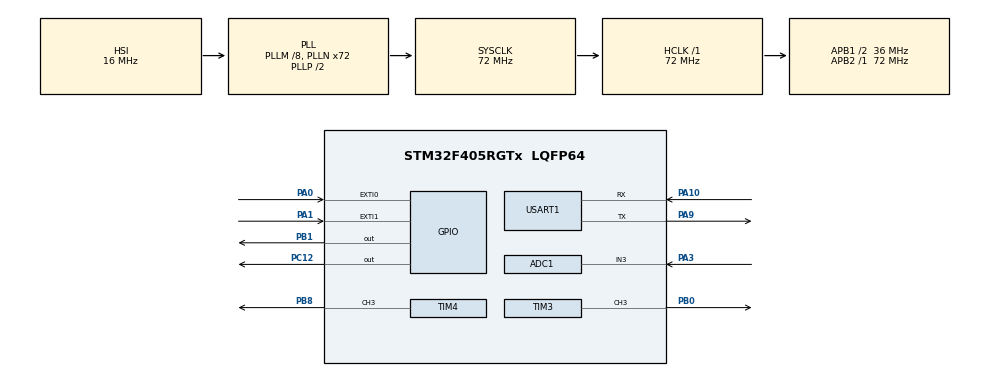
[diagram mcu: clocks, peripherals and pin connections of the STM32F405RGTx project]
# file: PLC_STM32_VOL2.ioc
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ADC1.Channel-0\#ChannelRegularConversion=ADC_CHANNEL_3
ADC1.ExternalTrigConv=ADC_EXTERNALTRIGCONV_T1_CC1
ADC1.NbrOfConversionFlag=1
ADC1.Rank-0\#ChannelRegularConversion=1
ADC1.SamplingTime-0\#ChannelRegularConversion=ADC_SAMPLETIME_3CYCLES
ADC1.master=1
Dma.Request0=TIM3_CH4/UP
Dma.Request1=TIM4_UP
Dma.Request2=USART1_TX
Dma.Request3=TIM4_CH3
Dma.TIM3_CH4/UP.0.Direction=DMA_MEMORY_TO_PERIPH
Dma.TIM3_CH4/UP.0.FIFOMode=DMA_FIFOMODE_DISABLE
Dma.TIM3_CH4/UP.0.Instance=DMA1_Stream2
Dma.TIM3_CH4/UP.0.MemDataAlignment=DMA_MDATAALIGN_HALFWORD
Dma.TIM3_CH4/UP.0.MemInc=DMA_MINC_ENABLE
Dma.TIM3_CH4/UP.0.Mode=DMA_NORMAL
Dma.TIM3_CH4/UP.0.PeriphDataAlignment=DMA_PDATAALIGN_HALFWORD
Dma.TIM3_CH4/UP.0.PeriphInc=DMA_PINC_DISABLE
Dma.TIM3_CH4/UP.0.Priority=DMA_PRIORITY_LOW
Dma.TIM4_CH3.3.Direction=DMA_MEMORY_TO_PERIPH
Dma.TIM4_CH3.3.FIFOMode=DMA_FIFOMODE_DISABLE
Dma.TIM4_CH3.3.Instance=DMA1_Stream7
Dma.TIM4_CH3.3.MemDataAlignment=DMA_MDATAALIGN_HALFWORD
Dma.TIM4_CH3.3.MemInc=DMA_MINC_ENABLE
Dma.TIM4_CH3.3.Mode=DMA_NORMAL
Dma.TIM4_CH3.3.PeriphDataAlignment=DMA_PDATAALIGN_HALFWORD
Dma.TIM4_CH3.3.PeriphInc=DMA_PINC_DISABLE
Dma.TIM4_CH3.3.Priority=DMA_PRIORITY_LOW
Dma.TIM4_UP.1.Direction=DMA_MEMORY_TO_PERIPH
Dma.TIM4_UP.1.FIFOMode=DMA_FIFOMODE_DISABLE
Dma.TIM4_UP.1.Instance=DMA1_Stream6
Dma.TIM4_UP.1.MemDataAlignment=DMA_MDATAALIGN_HALFWORD
Dma.TIM4_UP.1.MemInc=DMA_MINC_ENABLE
Dma.TIM4_UP.1.Mode=DMA_NORMAL
Dma.TIM4_UP.1.PeriphDataAlignment=DMA_PDATAALIGN_HALFWORD
Dma.TIM4_UP.1.PeriphInc=DMA_PINC_DISABLE
Dma.TIM4_UP.1.Priority=DMA_PRIORITY_LOW
Dma.USART1_TX.2.Direction=DMA_MEMORY_TO_PERIPH
Dma.USART1_TX.2.FIFOMode=DMA_FIFOMODE_DISABLE
Dma.USART1_TX.2.Instance=DMA2_Stream7
Dma.USART1_TX.2.MemDataAlignment=DMA_MDATAALIGN_BYTE
Dma.USART1_TX.2.MemInc=DMA_MINC_ENABLE
Dma.USART1_TX.2.Mode=DMA_NORMAL
Dma.USART1_TX.2.PeriphDataAlignment=DMA_PDATAALIGN_BYTE
Dma.USART1_TX.2.PeriphInc=DMA_PINC_DISABLE
Dma.USART1_TX.2.Priority=DMA_PRIORITY_LOW
Mcu.Family=STM32F4
Mcu.Name=STM32F405RGTx
Mcu.Package=LQFP64
NVIC.ADC_IRQn=true\:0\:0\:false\:false\:true\:true\:true\:true
NVIC.DMA1_Stream2_IRQn=true\:0\:0\:false\:false\:true\:false\:true\:true
NVIC.DMA1_Stream6_IRQn=true\:0\:0\:false\:false\:true\:false\:true\:true
NVIC.DMA1_Stream7_IRQn=true\:0\:0\:false\:false\:true\:false\:true\:true
NVIC.DMA2_Stream7_IRQn=true\:0\:0\:false\:false\:true\:false\:true\:true
NVIC.PriorityGroup=NVIC_PRIORITYGROUP_4
NVIC.TIM1_TRG_COM_TIM11_IRQn=true\:0\:0\:false\:false\:true\:true\:true\:true
NVIC.TIM1_UP_TIM10_IRQn=true\:0\:0\:false\:false\:true\:true\:true\:true
NVIC.TIM2_IRQn=true\:0\:0\:false\:false\:true\:true\:true\:true
NVIC.TIM3_IRQn=true\:0\:0\:false\:false\:true\:true\:true\:true
NVIC.TIM4_IRQn=true\:0\:0\:false\:false\:true\:true\:true\:true
NVIC.TIM5_IRQn=true\:0\:0\:false\:false\:true\:true\:true\:true
NVIC.TIM7_IRQn=true\:0\:0\:false\:false\:true\:true\:true\:true
NVIC.USART1_IRQn=true\:0\:0\:false\:false\:true\:true\:true\:true
PA0-WKUP.Signal=GPXTI0
PA1.GPIO_PuPd=GPIO_PULLUP
PA1.Signal=GPXTI1
PA10.Mode=Asynchronous
PA10.Signal=USART1_RX
PA13.Mode=Serial_Wire
PA13.Signal=SYS_JTMS-SWDIO
PA14.Mode=Serial_Wire
PA14.Signal=SYS_JTCK-SWCLK
PA3.Signal=ADCx_IN3
PA9.Mode=Asynchronous
PA9.Signal=USART1_TX
PB0.Signal=S_TIM3_CH3
PB1.Signal=GPIO_Output
PB8.Signal=S_TIM4_CH3
PC12.Signal=GPIO_Output
PC14-OSC32_IN.Mode=LSE-External-Oscillator
PC14-OSC32_IN.Signal=RCC_OSC32_IN
PC15-OSC32_OUT.Mode=LSE-External-Oscillator
PC15-OSC32_OUT.Signal=RCC_OSC32_OUT
PH0-OSC_IN.Mode=HSE-External-Oscillator
PH0-OSC_IN.Signal=RCC_OSC_IN
PH1-OSC_OUT.Mode=HSE-External-Oscillator
PH1-OSC_OUT.Signal=RCC_OSC_OUT
ProjectManager.HeapSize=0x200
ProjectManager.StackSize=0x400
ProjectManager.TargetToolchain=STM32CubeIDE
RCC.48MHZClocksFreq_Value=36000000
RCC.AHBFreq_Value=72000000
RCC.APB1CLKDivider=RCC_HCLK_DIV2
RCC.APB1Freq_Value=36000000
RCC.APB1TimFreq_Value=72000000
RCC.APB2Freq_Value=72000000
RCC.APB2TimFreq_Value=72000000
RCC.CortexFreq_Value=72000000
RCC.HCLKFreq_Value=72000000
RCC.HSE_VALUE=25000000
RCC.HSI_VALUE=16000000
RCC.PLLM=8
RCC.PLLN=72
RCC.SYSCLKFreq_VALUE=72000000
RCC.SYSCLKSource=RCC_SYSCLKSOURCE_PLLCLK
RCC.VCOOutputFreq_Value=144000000
SH.ADCx_IN3.0=ADC1_IN3,IN3
SH.S_TIM3_CH3.0=TIM3_CH3,Output Compare3 CH3
SH.S_TIM4_CH3.0=TIM4_CH3,Output Compare3 CH3
TIM1.Channel-Output\ Compare1\ No\ Output=TIM_CHANNEL_1
TIM1.OCMode_1=TIM_OCMODE_TOGGLE
TIM1.Period=10
TIM1.Prescaler=719
TIM10.Period=50
TIM10.Prescaler=71
TIM2.Channel-Output\ Compare1\ No\ Output=TIM_CHANNEL_1
TIM2.OCMode_1=TIM_OCMODE_ACTIVE
TIM2.Pulse-Output\ Compare1\ No\ Output=4294967295
TIM3.Channel-Output\ Compare3\ CH3=TIM_CHANNEL_3
TIM3.OCMode_3=TIM_OCMODE_TOGGLE
TIM3.Period=1
TIM3.Prescaler=719
TIM3.TIM_MasterOutputTrigger=TIM_TRGO_UPDATE
TIM4.Channel-Output\ Compare3\ CH3=TIM_CHANNEL_3
TIM4.OCMode_3=TIM_OCMODE_TOGGLE
TIM4.Period=1
TIM4.Prescaler=719
TIM4.TIM_MasterOutputTrigger=TIM_TRGO_UPDATE
TIM5.Channel-Output\ Compare1\ No\ Output=TIM_CHANNEL_1
TIM5.OCMode_1=TIM_OCMODE_ACTIVE
TIM5.Pulse-Output\ Compare1\ No\ Output=4294967295
TIM7.Period=999
TIM7.Prescaler=7219
USART1.VirtualMode=VM_ASYNC
VP_TIM10_VS_ClockSourceINT.Mode=Enable_Timer
VP_TIM1_VS_no_output1.Mode=Output Compare1 No Output
VP_TIM2_VS_ClockSourceITR.Mode=TriggerSource_ITR2
VP_TIM2_VS_ControllerModeClock.Mode=Clock Mode
VP_TIM2_VS_no_output1.Mode=Output Compare1 No Output
VP_TIM3_VS_ClockSourceINT.Mode=Internal
VP_TIM4_VS_ClockSourceINT.Mode=Internal
VP_TIM5_VS_ClockSourceITR.Mode=TriggerSource_ITR2
VP_TIM5_VS_ControllerModeClock.Mode=Clock Mode
VP_TIM5_VS_no_output1.Mode=Output Compare1 No Output
VP_TIM7_VS_ClockSourceINT.Mode=Enable_Timer
board=custom

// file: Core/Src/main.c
/* USER CODE BEGIN Header */
/**
  ******************************************************************************
  * @file           : main.c
  * @brief          : Main program body
  ******************************************************************************
  * @attention
  *
  * Copyright (c) 2023 STMicroelectronics.
  * All rights reserved.
  *
  * This software is licensed under terms that can be found in the LICENSE file
  * in the root directory of this software component.
  * If no LICENSE file comes with this software, it is provided AS-IS.
  *
  ******************************************************************************
  */
/* USER CODE END Header */
#include "main.h"

/* USER CODE BEGIN Includes */
#include "hmi_interface.h"

#if MODBUS_ENABLE
#include "mb.h"
#include "mbport.h"
#include "mt_port.h"
#endif

#if DWIN_SERIAL_PORT_ENABLE
#include "DWIN_lib.h"
#include "DWIN_port.h"
#endif

/* USER CODE END Includes */

ADC_HandleTypeDef hadc1;

TIM_HandleTypeDef htim1;
TIM_HandleTypeDef htim2;
TIM_HandleTypeDef htim3;
TIM_HandleTypeDef htim4;
TIM_HandleTypeDef htim5;
TIM_HandleTypeDef htim7;
TIM_HandleTypeDef htim10;
DMA_HandleTypeDef hdma_tim3_ch4_up;
DMA_HandleTypeDef hdma_tim4_up;
DMA_HandleTypeDef hdma_tim4_ch3;

UART_HandleTypeDef huart1;
DMA_HandleTypeDef hdma_usart1_tx;

/* USER CODE BEGIN PV */
extern t_control ctrl;
extern uint8_t start;
extern uint8_t print;
extern t_step_engine step_engines[2];

prog_dscrptr programms[MAX_PRGRMS_NUM];

t_vac_sen vac_sensor;
t_vac_pump vac_pump;
t_dac dac;
t_bldc_engine bldc_engine;

#if MODBUS_ENABLE
extern t_modbus_him_pack rxData;
extern t_modbus_him_pack txData;

extern uint16_t rx_data[256];
extern uint8_t rx_data_indx;

static USHORT usRegHoldingStart = REG_HOLDING_START;
static int usRegHoldingBuf[REG_HOLDING_NREGS] = { 0x0 };

static USHORT usRegInputStart = REG_INPUT_START;
static USHORT usRegInputBuf[REG_INPUT_NREGS] = { 0x0 };
#endif

#if DWIN_SERIAL_PORT_ENABLE
extern volatile USHORT  ucRegistersBuf[DWIN_SER_PDU_SIZE_MAX];
extern volatile UCHAR  ucDWINBuf[DWIN_SER_PDU_SIZE_MAX];
#endif
extern uint16_t in_count;
uint8_t is_start_pos = 0x0;

t_devices dev;
/* USER CODE END PV */

void SystemClock_Config(void);
static void MX_GPIO_Init(void);
static void MX_DMA_Init(void);
static void MX_ADC1_Init(void);
static void MX_TIM1_Init(void);
static void MX_TIM2_Init(void);
static void MX_TIM3_Init(void);
static void MX_TIM4_Init(void);
static void MX_TIM5_Init(void);
static void MX_TIM10_Init(void);
static void MX_USART1_UART_Init(void);
static void MX_TIM7_Init(void);

/* USER CODE BEGIN 0 */
uint8_t cnt = 0;

#if SEND_CURV_TEST
void DataWrite(uint16_t data, uint8_t curve) {
	uint8_t low_byte = data;
	data = data >> 8;
	uint8_t high_byte = data;

	uint8_t mdata[14] = { 0x00 };
	mdata[0] = 0x5A;
	mdata[1] = 0xA5;
	mdata[2] = 0x0B;
	mdata[3] = 0x82;
	mdata[4] = 0x03;
	mdata[5] = 0x10;
	mdata[6] = 0x5A;
	mdata[7] = 0xA5;
	mdata[8] = 0x01;
	mdata[9] = 0x00;
	mdata[10] = curve;
	mdata[11] = 0x01;
	mdata[12] = high_byte;
	mdata[13] = low_byte;

	HAL_UART_Transmit(&huart1, mdata, 14, 300);

}
#endif

void init_Test_Time(void) {
	/* Проверка работы на осциллографе */

	RCC->AHB1ENR |= RCC_AHB1ENR_GPIOAEN; //Enable GPIOA

	/* PA7 - шип 1 */
	GPIOA->MODER &= ~GPIO_MODER_MODE7;
	GPIOA->MODER |= GPIO_MODER_MODE7_0; //Output mode
	GPIOA->OSPEEDR |= GPIO_OSPEEDER_OSPEEDR7_1;

	/*
	 * GPIOA->BSRR |= GPIO_BSRR_BR7; reset
	 * GPIOA->BSRR |= GPIO_BSRR_BS7; set
	 * */

}

void func_hard_fault(void);

void func_hard_fault(void) //Функция, вызов которой приведет к отказу
{
  while(1) continue;
}

/* USER CODE END 0 */

int main(void)
{
  /* USER CODE BEGIN 1 */

//	void (*ptr_hard_fault_func) (void); //Объявляем указатель на функцию отказа
//	ptr_hard_fault_func = (((uint8_t* )func_hard_fault) - 1); //Присваиваем ему значение со сброшенным младшим битом
//	ptr_hard_fault_func(); //Вызов функции отказа

  /* USER CODE END 1 */

  /* MCU Configuration--------------------------------------------------------*/

  /* Reset of all peripherals, Initializes the Flash interface and the Systick. */
  HAL_Init();

  /* Configure the system clock */
  SystemClock_Config();

  /* Initialize all configured peripherals */
  MX_GPIO_Init();
  MX_DMA_Init();
  MX_ADC1_Init();
  MX_TIM1_Init();
  MX_TIM2_Init();
  MX_TIM3_Init();
  MX_TIM4_Init();
  MX_TIM5_Init();
  MX_TIM10_Init();
  MX_USART1_UART_Init();
  MX_TIM7_Init();
  /* USER CODE BEGIN 2 */
  #if HAL_ADC_MODULE_ENABLED
  MX_ADC1_Init();
  #endif

  init_Test_Time();

	#if MODBUS_ENABLE

	MT_PORT_SetTimerModule(&htim10);
	MT_PORT_SetUartModule(&huart1);

	eMBErrorCode eStatus;
	//eStatus = eMBInit(MB_RTU, 0x0A, 0, 19200, MB_PAR_NONE);
	eStatus = eMBInit(MB_RTU, 0x01, 0, 115200, MB_PAR_NONE);
	eStatus = eMBEnable();
	if (eStatus != MB_ENOERR)
	{
	// Error handling
	}

	usRegHoldingBuf[NUM_EXE_PROGRAM] = 0x01;
	usRegHoldingBuf[STEP_ENGINE_VEL_MC] = 0x30;
	usRegHoldingBuf[STEP_ENGINE_START_POS_MS] = 0x51;

	usRegHoldingBuf[STAGE_1_POS] = 3600;
	usRegHoldingBuf[STAGE_1_VEL] = 360;

	#endif

	#if PEREPH_ENABLE

	/* Ring buffer init */
	t_ring_buf ring_buf;
	t_queue_dicr queue[RING_BUF_SIZE];

	t_RING_BUF_ErrorStatus rStatus = ringBuf_init(&ring_buf, queue, RING_BUF_SIZE);

	if (rStatus == RING_BUFFER_SUCCESS) {
		ctrl.queue = &ring_buf;
	}

	ctrl.dev = &dev;
	ctrl.programms = programms;

	ctrl.HMI_curves[0].refresh_rate = 10;
	ctrl.HMI_curves[0].tim = &htim7;

	init_HMI(&ctrl, ucRegistersBuf);
	#endif

	#if STEP_ENGINE_ENABLE
	//HAL_DBGMCU_EnableDBGStandbyMode();
  //HAL_DBGMCU_EnableDBGStopMode();
	//DBGMCU->APB1FZ |= DBGMCU_APB1_FZ_DBG_TIM3_STOP;
	HAL_GPIO_WritePin(GPIOC, GPIO_PIN_12, GPIO_PIN_SET);
	t_LSPort port;
	dev.step_engine = step_engines;

	/* Initial X-axes step engine */

	init_step_engine(&step_engines[0], &htim3, &htim2);

	port.port_letter = 'B';
	port.port_number = 7;

	limit_siwitch_init(&port);
//	step_engines[0].limit_switch = port;

	/* Initial Y-axes step engine */

	init_step_engine(&step_engines[1], &htim4, &htim5);

	port.port_letter = 'B';
	port.port_number = 9;

	limit_siwitch_init(&port);

//	step_engines[1].limit_switch = port;
	/* Limited switch init */

	#endif

	#if HAL_ADC_MODULE_ENABLED
		#if VACUUM_SENSOR_ENABLE
			init_vac_sens(&vac_sensor, &hadc1);
			dev.vac_sensor = &vac_sensor;
			init_vac_pump(&vac_pump, 100, 0x0);
			dev.vac_pump = &vac_pump;
		#endif
	#endif

	#if BLDC_ENGINE_ENABLE
	bldc_engine.power = 0;
	dev.bldc_engine = &bldc_engine;
	init_BLDC(dev.bldc_engine, &dac);
	#endif

	#if DAC_ENABLE
	/* DAC init */
	dev.bldc_engine->dac->tim = TIM6;
	dev.bldc_engine->dac->dac_type = DAC;
	dev.bldc_engine->dac->tim_presc = 719;
	dev.bldc_engine->dac->tim_arr = 7;
	CMSIS_DAC_init(dev.bldc_engine->dac);
	#endif

	#if DWIN_SERIAL_PORT_ENABLE

	DWIN_PORT_SetUartModule(&huart1);

	eDWINErrorCode eStatus;
	eDWINInit(0xA5, 0, 115200, DWIN_PAR_NONE);

	eStatus = eDWINEnable();
	if (eStatus != DWIN_ENOERR)
	{
	// Error handling
	}
	#endif

	HAL_ADC_Start_IT(&hadc1);
	HAL_TIM_OC_Start_IT(&htim1, TIM_CHANNEL_1);

  /* USER CODE END 2 */

  /* Infinite loop */
  /* USER CODE BEGIN WHILE */
  while (1)
  {
		#if PEREPH_ENABLE
			#if SEND_CURV_TEST
			cnt++;
			if (cnt >= 255) cnt = 0;
			DataWrite(cnt, 0x0);
			HAL_Delay(100);
			#endif

			#if DAC_ENABLE
			/*if (a > 4096){
				a = 0;
			}
			dac.dac_type->DHR12R1 = a;
			a++;
			*/
			#endif

			#if MODBUS_ENABLE
			eHMIPoll(&ctrl, usRegHoldingBuf);
			#endif

			#if DWIN_SERIAL_PORT_ENABLE
			eHMIPoll(&ctrl, ucRegistersBuf);
			#endif
		#endif

		#if MODBUS_ENABLE
		eMBPoll();
		#endif

		#if DWIN_SERIAL_PORT_ENABLE
		eDWINPoll();
		#endif

    /* USER CODE END WHILE */

  }
}

void SystemClock_Config(void)
{
  RCC_OscInitTypeDef RCC_OscInitStruct = {0};
  RCC_ClkInitTypeDef RCC_ClkInitStruct = {0};

  /** Configure the main internal regulator output voltage
  */
  __HAL_RCC_PWR_CLK_ENABLE();
  __HAL_PWR_VOLTAGESCALING_CONFIG(PWR_REGULATOR_VOLTAGE_SCALE1);
  /** Initializes the RCC Oscillators according to the specified parameters
  * in the RCC_OscInitTypeDef structure.
  */
  RCC_OscInitStruct.OscillatorType = RCC_OSCILLATORTYPE_HSI;
  RCC_OscInitStruct.HSIState = RCC_HSI_ON;
  RCC_OscInitStruct.HSICalibrationValue = RCC_HSICALIBRATION_DEFAULT;
  RCC_OscInitStruct.PLL.PLLState = RCC_PLL_ON;
  RCC_OscInitStruct.PLL.PLLSource = RCC_PLLSOURCE_HSI;
  RCC_OscInitStruct.PLL.PLLM = 8;
  RCC_OscInitStruct.PLL.PLLN = 72;
  RCC_OscInitStruct.PLL.PLLP = RCC_PLLP_DIV2;
  RCC_OscInitStruct.PLL.PLLQ = 4;
  if (HAL_RCC_OscConfig(&RCC_OscInitStruct) != HAL_OK)
  {
    Error_Handler();
  }
  /** Initializes the CPU, AHB and APB buses clocks
  */
  RCC_ClkInitStruct.ClockType = RCC_CLOCKTYPE_HCLK|RCC_CLOCKTYPE_SYSCLK
                              |RCC_CLOCKTYPE_PCLK1|RCC_CLOCKTYPE_PCLK2;
  RCC_ClkInitStruct.SYSCLKSource = RCC_SYSCLKSOURCE_PLLCLK;
  RCC_ClkInitStruct.AHBCLKDivider = RCC_SYSCLK_DIV1;
  RCC_ClkInitStruct.APB1CLKDivider = RCC_HCLK_DIV2;
  RCC_ClkInitStruct.APB2CLKDivider = RCC_HCLK_DIV1;

  if (HAL_RCC_ClockConfig(&RCC_ClkInitStruct, FLASH_LATENCY_2) != HAL_OK)
  {
    Error_Handler();
  }
}

static void MX_ADC1_Init(void)
{

  ADC_ChannelConfTypeDef sConfig = {0};

  /** Configure the global features of the ADC (Clock, Resolution, Data Alignment and number of conversion)
  */
  hadc1.Instance = ADC1;
  hadc1.Init.ClockPrescaler = ADC_CLOCK_SYNC_PCLK_DIV2;
  hadc1.Init.Resolution = ADC_RESOLUTION_12B;
  hadc1.Init.ScanConvMode = DISABLE;
  hadc1.Init.ContinuousConvMode = DISABLE;
  hadc1.Init.DiscontinuousConvMode = DISABLE;
  hadc1.Init.ExternalTrigConvEdge = ADC_EXTERNALTRIGCONVEDGE_RISING;
  hadc1.Init.ExternalTrigConv = ADC_EXTERNALTRIGCONV_T1_CC1;
  hadc1.Init.DataAlign = ADC_DATAALIGN_RIGHT;
  hadc1.Init.NbrOfConversion = 1;
  hadc1.Init.DMAContinuousRequests = DISABLE;
  hadc1.Init.EOCSelection = ADC_EOC_SINGLE_CONV;
  if (HAL_ADC_Init(&hadc1) != HAL_OK)
  {
    Error_Handler();
  }
  /** Configure for the selected ADC regular channel its corresponding rank in the sequencer and its sample time.
  */
  sConfig.Channel = ADC_CHANNEL_3;
  sConfig.Rank = 1;
  sConfig.SamplingTime = ADC_SAMPLETIME_3CYCLES;
  if (HAL_ADC_ConfigChannel(&hadc1, &sConfig) != HAL_OK)
  {
    Error_Handler();
  }

}

static void MX_TIM1_Init(void)
{

  TIM_MasterConfigTypeDef sMasterConfig = {0};
  TIM_OC_InitTypeDef sConfigOC = {0};
  TIM_BreakDeadTimeConfigTypeDef sBreakDeadTimeConfig = {0};

  htim1.Instance = TIM1;
  htim1.Init.Prescaler = 719;
  htim1.Init.CounterMode = TIM_COUNTERMODE_UP;
  htim1.Init.Period = 10;
  htim1.Init.ClockDivision = TIM_CLOCKDIVISION_DIV1;
  htim1.Init.RepetitionCounter = 0;
  htim1.Init.AutoReloadPreload = TIM_AUTORELOAD_PRELOAD_DISABLE;
  if (HAL_TIM_OC_Init(&htim1) != HAL_OK)
  {
    Error_Handler();
  }
  sMasterConfig.MasterOutputTrigger = TIM_TRGO_RESET;
  sMasterConfig.MasterSlaveMode = TIM_MASTERSLAVEMODE_DISABLE;
  if (HAL_TIMEx_MasterConfigSynchronization(&htim1, &sMasterConfig) != HAL_OK)
  {
    Error_Handler();
  }
  sConfigOC.OCMode = TIM_OCMODE_TOGGLE;
  sConfigOC.Pulse = 0;
  sConfigOC.OCPolarity = TIM_OCPOLARITY_HIGH;
  sConfigOC.OCNPolarity = TIM_OCNPOLARITY_HIGH;
  sConfigOC.OCFastMode = TIM_OCFAST_DISABLE;
  sConfigOC.OCIdleState = TIM_OCIDLESTATE_RESET;
  sConfigOC.OCNIdleState = TIM_OCNIDLESTATE_RESET;
  if (HAL_TIM_OC_ConfigChannel(&htim1, &sConfigOC, TIM_CHANNEL_1) != HAL_OK)
  {
    Error_Handler();
  }
  sBreakDeadTimeConfig.OffStateRunMode = TIM_OSSR_DISABLE;
  sBreakDeadTimeConfig.OffStateIDLEMode = TIM_OSSI_DISABLE;
  sBreakDeadTimeConfig.LockLevel = TIM_LOCKLEVEL_OFF;
  sBreakDeadTimeConfig.DeadTime = 0;
  sBreakDeadTimeConfig.BreakState = TIM_BREAK_DISABLE;
  sBreakDeadTimeConfig.BreakPolarity = TIM_BREAKPOLARITY_HIGH;
  sBreakDeadTimeConfig.AutomaticOutput = TIM_AUTOMATICOUTPUT_DISABLE;
  if (HAL_TIMEx_ConfigBreakDeadTime(&htim1, &sBreakDeadTimeConfig) != HAL_OK)
  {
    Error_Handler();
  }

}

static void MX_TIM2_Init(void)
{

  TIM_SlaveConfigTypeDef sSlaveConfig = {0};
  TIM_MasterConfigTypeDef sMasterConfig = {0};
  TIM_OC_InitTypeDef sConfigOC = {0};

  htim2.Instance = TIM2;
  htim2.Init.Prescaler = 0;
  htim2.Init.CounterMode = TIM_COUNTERMODE_UP;
  htim2.Init.Period = 4294967295;
  htim2.Init.ClockDivision = TIM_CLOCKDIVISION_DIV1;
  htim2.Init.AutoReloadPreload = TIM_AUTORELOAD_PRELOAD_DISABLE;
  if (HAL_TIM_Base_Init(&htim2) != HAL_OK)
  {
    Error_Handler();
  }
  if (HAL_TIM_OC_Init(&htim2) != HAL_OK)
  {
    Error_Handler();
  }
  sSlaveConfig.SlaveMode = TIM_SLAVEMODE_EXTERNAL1;
  sSlaveConfig.InputTrigger = TIM_TS_ITR2;
  if (HAL_TIM_SlaveConfigSynchro(&htim2, &sSlaveConfig) != HAL_OK)
  {
    Error_Handler();
  }
  sMasterConfig.MasterOutputTrigger = TIM_TRGO_RESET;
  sMasterConfig.MasterSlaveMode = TIM_MASTERSLAVEMODE_DISABLE;
  if (HAL_TIMEx_MasterConfigSynchronization(&htim2, &sMasterConfig) != HAL_OK)
  {
    Error_Handler();
  }
  sConfigOC.OCMode = TIM_OCMODE_ACTIVE;
  sConfigOC.Pulse = 4294967295;
  sConfigOC.OCPolarity = TIM_OCPOLARITY_HIGH;
  sConfigOC.OCFastMode = TIM_OCFAST_DISABLE;
  if (HAL_TIM_OC_ConfigChannel(&htim2, &sConfigOC, TIM_CHANNEL_1) != HAL_OK)
  {
    Error_Handler();
  }

}

static void MX_TIM3_Init(void)
{

  TIM_ClockConfigTypeDef sClockSourceConfig = {0};
  TIM_MasterConfigTypeDef sMasterConfig = {0};
  TIM_OC_InitTypeDef sConfigOC = {0};

  htim3.Instance = TIM3;
  htim3.Init.Prescaler = 719;
  htim3.Init.CounterMode = TIM_COUNTERMODE_UP;
  htim3.Init.Period = 1;
  htim3.Init.ClockDivision = TIM_CLOCKDIVISION_DIV1;
  htim3.Init.AutoReloadPreload = TIM_AUTORELOAD_PRELOAD_DISABLE;
  if (HAL_TIM_Base_Init(&htim3) != HAL_OK)
  {
    Error_Handler();
  }
  sClockSourceConfig.ClockSource = TIM_CLOCKSOURCE_INTERNAL;
  if (HAL_TIM_ConfigClockSource(&htim3, &sClockSourceConfig) != HAL_OK)
  {
    Error_Handler();
  }
  if (HAL_TIM_OC_Init(&htim3) != HAL_OK)
  {
    Error_Handler();
  }
  sMasterConfig.MasterOutputTrigger = TIM_TRGO_UPDATE;
  sMasterConfig.MasterSlaveMode = TIM_MASTERSLAVEMODE_DISABLE;
  if (HAL_TIMEx_MasterConfigSynchronization(&htim3, &sMasterConfig) != HAL_OK)
  {
    Error_Handler();
  }
  sConfigOC.OCMode = TIM_OCMODE_TOGGLE;
  sConfigOC.Pulse = 0;
  sConfigOC.OCPolarity = TIM_OCPOLARITY_HIGH;
  sConfigOC.OCFastMode = TIM_OCFAST_DISABLE;
  if (HAL_TIM_OC_ConfigChannel(&htim3, &sConfigOC, TIM_CHANNEL_3) != HAL_OK)
  {
    Error_Handler();
  }
  HAL_TIM_MspPostInit(&htim3);

}

static void MX_TIM4_Init(void)
{

  TIM_ClockConfigTypeDef sClockSourceConfig = {0};
  TIM_MasterConfigTypeDef sMasterConfig = {0};
  TIM_OC_InitTypeDef sConfigOC = {0};

  htim4.Instance = TIM4;
  htim4.Init.Prescaler = 719;
  htim4.Init.CounterMode = TIM_COUNTERMODE_UP;
  htim4.Init.Period = 1;
  htim4.Init.ClockDivision = TIM_CLOCKDIVISION_DIV1;
  htim4.Init.AutoReloadPreload = TIM_AUTORELOAD_PRELOAD_DISABLE;
  if (HAL_TIM_Base_Init(&htim4) != HAL_OK)
  {
    Error_Handler();
  }
  sClockSourceConfig.ClockSource = TIM_CLOCKSOURCE_INTERNAL;
  if (HAL_TIM_ConfigClockSource(&htim4, &sClockSourceConfig) != HAL_OK)
  {
    Error_Handler();
  }
  if (HAL_TIM_OC_Init(&htim4) != HAL_OK)
  {
    Error_Handler();
  }
  sMasterConfig.MasterOutputTrigger = TIM_TRGO_UPDATE;
  sMasterConfig.MasterSlaveMode = TIM_MASTERSLAVEMODE_DISABLE;
  if (HAL_TIMEx_MasterConfigSynchronization(&htim4, &sMasterConfig) != HAL_OK)
  {
    Error_Handler();
  }
  sConfigOC.OCMode = TIM_OCMODE_TOGGLE;
  sConfigOC.Pulse = 0;
  sConfigOC.OCPolarity = TIM_OCPOLARITY_HIGH;
  sConfigOC.OCFastMode = TIM_OCFAST_DISABLE;
  if (HAL_TIM_OC_ConfigChannel(&htim4, &sConfigOC, TIM_CHANNEL_3) != HAL_OK)
  {
    Error_Handler();
  }
  HAL_TIM_MspPostInit(&htim4);

}

static void MX_TIM5_Init(void)
{

  TIM_SlaveConfigTypeDef sSlaveConfig = {0};
  TIM_MasterConfigTypeDef sMasterConfig = {0};
  TIM_OC_InitTypeDef sConfigOC = {0};

  htim5.Instance = TIM5;
  htim5.Init.Prescaler = 0;
  htim5.Init.CounterMode = TIM_COUNTERMODE_UP;
  htim5.Init.Period = 4294967295;
  htim5.Init.ClockDivision = TIM_CLOCKDIVISION_DIV1;
  htim5.Init.AutoReloadPreload = TIM_AUTORELOAD_PRELOAD_DISABLE;
  if (HAL_TIM_Base_Init(&htim5) != HAL_OK)
  {
    Error_Handler();
  }
  if (HAL_TIM_OC_Init(&htim5) != HAL_OK)
  {
    Error_Handler();
  }
  sSlaveConfig.SlaveMode = TIM_SLAVEMODE_EXTERNAL1;
  sSlaveConfig.InputTrigger = TIM_TS_ITR2;
  if (HAL_TIM_SlaveConfigSynchro(&htim5, &sSlaveConfig) != HAL_OK)
  {
    Error_Handler();
  }
  sMasterConfig.MasterOutputTrigger = TIM_TRGO_RESET;
  sMasterConfig.MasterSlaveMode = TIM_MASTERSLAVEMODE_DISABLE;
  if (HAL_TIMEx_MasterConfigSynchronization(&htim5, &sMasterConfig) != HAL_OK)
  {
    Error_Handler();
  }
  sConfigOC.OCMode = TIM_OCMODE_ACTIVE;
  sConfigOC.Pulse = 4294967295;
  sConfigOC.OCPolarity = TIM_OCPOLARITY_HIGH;
  sConfigOC.OCFastMode = TIM_OCFAST_DISABLE;
  if (HAL_TIM_OC_ConfigChannel(&htim5, &sConfigOC, TIM_CHANNEL_1) != HAL_OK)
  {
    Error_Handler();
  }

}

static void MX_TIM7_Init(void)
{

  TIM_MasterConfigTypeDef sMasterConfig = {0};

  htim7.Instance = TIM7;
  htim7.Init.Prescaler = 7219;
  htim7.Init.CounterMode = TIM_COUNTERMODE_UP;
  htim7.Init.Period = 999;
  htim7.Init.AutoReloadPreload = TIM_AUTORELOAD_PRELOAD_DISABLE;
  if (HAL_TIM_Base_Init(&htim7) != HAL_OK)
  {
    Error_Handler();
  }
  sMasterConfig.MasterOutputTrigger = TIM_TRGO_RESET;
  sMasterConfig.MasterSlaveMode = TIM_MASTERSLAVEMODE_DISABLE;
  if (HAL_TIMEx_MasterConfigSynchronization(&htim7, &sMasterConfig) != HAL_OK)
  {
    Error_Handler();
  }

}

static void MX_TIM10_Init(void)
{

  htim10.Instance = TIM10;
  htim10.Init.Prescaler = 71;
  htim10.Init.CounterMode = TIM_COUNTERMODE_UP;
  htim10.Init.Period = 50;
  htim10.Init.ClockDivision = TIM_CLOCKDIVISION_DIV1;
  htim10.Init.AutoReloadPreload = TIM_AUTORELOAD_PRELOAD_DISABLE;
  if (HAL_TIM_Base_Init(&htim10) != HAL_OK)
  {
    Error_Handler();
  }

}

static void MX_USART1_UART_Init(void)
{

  huart1.Instance = USART1;
  huart1.Init.BaudRate = 115200;
  huart1.Init.WordLength = UART_WORDLENGTH_8B;
  huart1.Init.StopBits = UART_STOPBITS_1;
  huart1.Init.Parity = UART_PARITY_NONE;
  huart1.Init.Mode = UART_MODE_TX_RX;
  huart1.Init.HwFlowCtl = UART_HWCONTROL_NONE;
  huart1.Init.OverSampling = UART_OVERSAMPLING_16;
  if (HAL_UART_Init(&huart1) != HAL_OK)
  {
    Error_Handler();
  }

}

static void MX_DMA_Init(void)
{

  /* DMA controller clock enable */
  __HAL_RCC_DMA1_CLK_ENABLE();
  __HAL_RCC_DMA2_CLK_ENABLE();

  /* DMA interrupt init */
  /* DMA1_Stream2_IRQn interrupt configuration */
  HAL_NVIC_SetPriority(DMA1_Stream2_IRQn, 0, 0);
  HAL_NVIC_EnableIRQ(DMA1_Stream2_IRQn);
  /* DMA1_Stream6_IRQn interrupt configuration */
  HAL_NVIC_SetPriority(DMA1_Stream6_IRQn, 0, 0);
  HAL_NVIC_EnableIRQ(DMA1_Stream6_IRQn);
  /* DMA1_Stream7_IRQn interrupt configuration */
  HAL_NVIC_SetPriority(DMA1_Stream7_IRQn, 0, 0);
  HAL_NVIC_EnableIRQ(DMA1_Stream7_IRQn);
  /* DMA2_Stream7_IRQn interrupt configuration */
  HAL_NVIC_SetPriority(DMA2_Stream7_IRQn, 0, 0);
  HAL_NVIC_EnableIRQ(DMA2_Stream7_IRQn);

}

static void MX_GPIO_Init(void)
{
  GPIO_InitTypeDef GPIO_InitStruct = {0};

  /* GPIO Ports Clock Enable */
  __HAL_RCC_GPIOC_CLK_ENABLE();
  __HAL_RCC_GPIOH_CLK_ENABLE();
  __HAL_RCC_GPIOA_CLK_ENABLE();
  __HAL_RCC_GPIOB_CLK_ENABLE();

  /*Configure GPIO pin Output Level */
  HAL_GPIO_WritePin(GPIOB, GPIO_PIN_1, GPIO_PIN_RESET);

  /*Configure GPIO pin Output Level */
  HAL_GPIO_WritePin(GPIOC, GPIO_PIN_12, GPIO_PIN_RESET);

  /*Configure GPIO pin : PA0 */
  GPIO_InitStruct.Pin = GPIO_PIN_0;
  GPIO_InitStruct.Mode = GPIO_MODE_IT_RISING;
  GPIO_InitStruct.Pull = GPIO_NOPULL;
  HAL_GPIO_Init(GPIOA, &GPIO_InitStruct);

  /*Configure GPIO pin : PA1 */
  GPIO_InitStruct.Pin = GPIO_PIN_1;
  GPIO_InitStruct.Mode = GPIO_MODE_IT_RISING;
  GPIO_InitStruct.Pull = GPIO_PULLUP;
  HAL_GPIO_Init(GPIOA, &GPIO_InitStruct);

  /*Configure GPIO pin : PB1 */
  GPIO_InitStruct.Pin = GPIO_PIN_1;
  GPIO_InitStruct.Mode = GPIO_MODE_OUTPUT_PP;
  GPIO_InitStruct.Pull = GPIO_NOPULL;
  GPIO_InitStruct.Speed = GPIO_SPEED_FREQ_LOW;
  HAL_GPIO_Init(GPIOB, &GPIO_InitStruct);

  /*Configure GPIO pin : PC12 */
  GPIO_InitStruct.Pin = GPIO_PIN_12;
  GPIO_InitStruct.Mode = GPIO_MODE_OUTPUT_PP;
  GPIO_InitStruct.Pull = GPIO_NOPULL;
  GPIO_InitStruct.Speed = GPIO_SPEED_FREQ_LOW;
  HAL_GPIO_Init(GPIOC, &GPIO_InitStruct);

  /*Configure GPIO pins : PB7 PB9 */
  GPIO_InitStruct.Pin = GPIO_PIN_7|GPIO_PIN_9;
  GPIO_InitStruct.Mode = GPIO_MODE_IT_RISING;
  GPIO_InitStruct.Pull = GPIO_PULLUP;
  HAL_GPIO_Init(GPIOB, &GPIO_InitStruct);

}

/* USER CODE BEGIN 4 */

void HAL_GPIO_EXTI_Callback(uint16_t GPIO_Pin)
{
	is_start_pos = 0x01;
}
/* USER CODE END 4 */

void Error_Handler(void)
{
  __disable_irq();
  while (1)
  {
  }
}

/************************ (C) COPYRIGHT STMicroelectronics *****END OF FILE****/
